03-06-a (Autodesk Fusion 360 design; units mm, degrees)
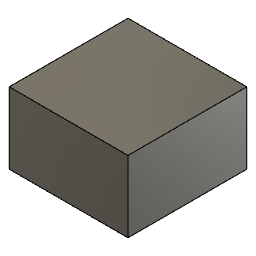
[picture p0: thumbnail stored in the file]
box_primitive "直方体プリミティブ" DistanceX 50 DistanceY 50 DistanceZ 30 OffsetDistanceX 0 OffsetDistanceY 0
